# Generated by innovus_enablement/scripts/gen_innovus_lef.py from ../i3dPDK_NS3K/TECH/i3dPDK_NS3K_5T_mw.tf
# i3dPDK_NS3K v1.1 (CC BY-NC-SA 4.0, Prof. Taigon Song, I3D VLSI Lab, KNU)
# NOT part of the original PDK. Directions and R/C are
# assumptions (see gen_innovus_lef.py ASSUMPTIONS).
VERSION 5.8 ;
BUSBITCHARS "[]" ;
DIVIDERCHAR "/" ;

UNITS
  DATABASE MICRONS 2000 ;
END UNITS
MANUFACTURINGGRID 0.0005 ;

# Unidirectional variant: M2 M3 M4 preferred direction only, on track (see UNIDIR_*).
# Strictly unidirectional variant of i3dPDK_NS3K_5T_tech_unidir.lef (TECH_LEF=..., experiments):
# every metal from M5 up also takes RIGHTWAYONGRIDONLY + RECTONLY, so NanoRoute routes M2-M11 in the preferred
# direction only, on track, like the ICC2 flow (M5+ track offsets unchanged). 1x geometry (lef_x4/: 4x).
PROPERTYDEFINITIONS
  LAYER LEF58_RIGHTWAYONGRIDONLY STRING ;
  LAYER LEF58_RECTONLY STRING ;
END PROPERTYDEFINITIONS

SITE i3d_nsfet3nm
  CLASS CORE ;
  SYMMETRY Y ;
  SIZE 0.044 BY 0.12 ;
END i3d_nsfet3nm

SITE i3d_nsfet3nm_2H_VDD
  CLASS CORE ;
  SYMMETRY Y ;
  SIZE 0.044 BY 0.24 ;
END i3d_nsfet3nm_2H_VDD

SITE i3d_nsfet3nm_2H_VSS
  CLASS CORE ;
  SYMMETRY Y ;
  SIZE 0.044 BY 0.24 ;
END i3d_nsfet3nm_2H_VSS

SITE i3d_nsfet3nm_3H_VDD
  CLASS CORE ;
  SYMMETRY Y ;
  SIZE 0.044 BY 0.36 ;
END i3d_nsfet3nm_3H_VDD

SITE i3d_nsfet3nm_3H_VSS
  CLASS CORE ;
  SYMMETRY Y ;
  SIZE 0.044 BY 0.36 ;
END i3d_nsfet3nm_3H_VSS

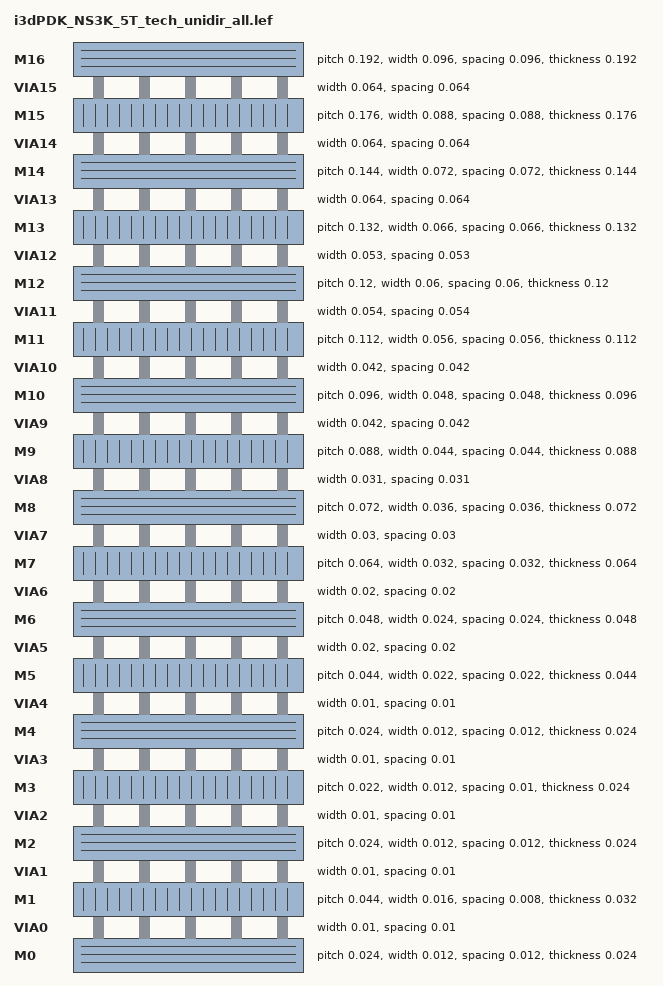
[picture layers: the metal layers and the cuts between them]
LAYER M0
  TYPE ROUTING ;
  DIRECTION HORIZONTAL ;
  PITCH 0.024 ;
  OFFSET 0.012 ;
  WIDTH 0.012 ;
  MINWIDTH 0.012 ;
  HEIGHT 0 ;
  THICKNESS 0.024 ;
  MAXWIDTH 5 ;
  SPACING 0.012 ;
  AREA 0.000144 ;
  RESISTANCE RPERSQ 8.0000 ;
  CAPACITANCE CPERSQDIST 0.00300000 ;
  EDGECAPACITANCE 0.00008000 ;
END M0

LAYER VIA0
  TYPE CUT ;
  WIDTH 0.01 ;
  SPACING 0.01 ;
  RESISTANCE 50.0000 ;
END VIA0

LAYER M1
  TYPE ROUTING ;
  DIRECTION VERTICAL ;
  PITCH 0.044 ;
  OFFSET 0.022 ;
  WIDTH 0.016 ;
  MINWIDTH 0.016 ;
  HEIGHT 0.048 ;
  THICKNESS 0.032 ;
  MAXWIDTH 5 ;
  SPACING 0.008 ;
  AREA 0.000256 ;
  RESISTANCE RPERSQ 8.0000 ;
  CAPACITANCE CPERSQDIST 0.00300000 ;
  EDGECAPACITANCE 0.00008000 ;
END M1

LAYER VIA1
  TYPE CUT ;
  WIDTH 0.01 ;
  SPACING 0.01 ;
  RESISTANCE 50.0000 ;
END VIA1

LAYER M2
  TYPE ROUTING ;
  DIRECTION HORIZONTAL ;
  PITCH 0.024 ;
  OFFSET 0 ;
  WIDTH 0.012 ;
  MINWIDTH 0.012 ;
  HEIGHT 0.112 ;
  THICKNESS 0.024 ;
  MAXWIDTH 5 ;
  SPACING 0.012 ;
  AREA 0.000144 ;
  RESISTANCE RPERSQ 8.0000 ;
  CAPACITANCE CPERSQDIST 0.00300000 ;
  EDGECAPACITANCE 0.00008000 ;
  PROPERTY LEF58_RIGHTWAYONGRIDONLY "RIGHTWAYONGRIDONLY ;" ;
  PROPERTY LEF58_RECTONLY "RECTONLY ;" ;
END M2

LAYER VIA2
  TYPE CUT ;
  WIDTH 0.01 ;
  SPACING 0.01 ;
  RESISTANCE 50.0000 ;
END VIA2

LAYER M3
  TYPE ROUTING ;
  DIRECTION VERTICAL ;
  PITCH 0.022 ;
  OFFSET 0 ;
  WIDTH 0.012 ;
  MINWIDTH 0.012 ;
  HEIGHT 0.16 ;
  THICKNESS 0.024 ;
  MAXWIDTH 5 ;
  SPACING 0.01 ;
  AREA 0.000144 ;
  RESISTANCE RPERSQ 8.0000 ;
  CAPACITANCE CPERSQDIST 0.00300000 ;
  EDGECAPACITANCE 0.00008000 ;
  PROPERTY LEF58_RIGHTWAYONGRIDONLY "RIGHTWAYONGRIDONLY ;" ;
  PROPERTY LEF58_RECTONLY "RECTONLY ;" ;
END M3

LAYER VIA3
  TYPE CUT ;
  WIDTH 0.01 ;
  SPACING 0.01 ;
  RESISTANCE 50.0000 ;
END VIA3

LAYER M4
  TYPE ROUTING ;
  DIRECTION HORIZONTAL ;
  PITCH 0.024 ;
  OFFSET 0 ;
  WIDTH 0.012 ;
  MINWIDTH 0.012 ;
  HEIGHT 0.208 ;
  THICKNESS 0.024 ;
  MAXWIDTH 5 ;
  SPACING 0.012 ;
  AREA 0.000144 ;
  RESISTANCE RPERSQ 1.2000 ;
  CAPACITANCE CPERSQDIST 0.00200000 ;
  EDGECAPACITANCE 0.00007000 ;
  PROPERTY LEF58_RIGHTWAYONGRIDONLY "RIGHTWAYONGRIDONLY ;" ;
  PROPERTY LEF58_RECTONLY "RECTONLY ;" ;
END M4

LAYER VIA4
  TYPE CUT ;
  WIDTH 0.01 ;
  SPACING 0.01 ;
  RESISTANCE 15.0000 ;
END VIA4

LAYER M5
  TYPE ROUTING ;
  DIRECTION VERTICAL ;
  PITCH 0.044 ;
  OFFSET 0.022 ;
  WIDTH 0.022 ;
  MINWIDTH 0.022 ;
  HEIGHT 0.256 ;
  THICKNESS 0.044 ;
  MAXWIDTH 5 ;
  SPACING 0.022 ;
  AREA 0.000484 ;
  RESISTANCE RPERSQ 1.2000 ;
  CAPACITANCE CPERSQDIST 0.00200000 ;
  EDGECAPACITANCE 0.00007000 ;
  PROPERTY LEF58_RIGHTWAYONGRIDONLY "RIGHTWAYONGRIDONLY ;" ;
  PROPERTY LEF58_RECTONLY "RECTONLY ;" ;
END M5

LAYER VIA5
  TYPE CUT ;
  WIDTH 0.02 ;
  SPACING 0.02 ;
  RESISTANCE 15.0000 ;
END VIA5

LAYER M6
  TYPE ROUTING ;
  DIRECTION HORIZONTAL ;
  PITCH 0.048 ;
  OFFSET 0.024 ;
  WIDTH 0.024 ;
  MINWIDTH 0.024 ;
  HEIGHT 0.344 ;
  THICKNESS 0.048 ;
  MAXWIDTH 5 ;
  SPACING 0.024 ;
  AREA 0.000576 ;
  RESISTANCE RPERSQ 1.2000 ;
  CAPACITANCE CPERSQDIST 0.00200000 ;
  EDGECAPACITANCE 0.00007000 ;
  PROPERTY LEF58_RIGHTWAYONGRIDONLY "RIGHTWAYONGRIDONLY ;" ;
  PROPERTY LEF58_RECTONLY "RECTONLY ;" ;
END M6

LAYER VIA6
  TYPE CUT ;
  WIDTH 0.02 ;
  SPACING 0.02 ;
  RESISTANCE 15.0000 ;
END VIA6

LAYER M7
  TYPE ROUTING ;
  DIRECTION VERTICAL ;
  PITCH 0.064 ;
  OFFSET 0.032 ;
  WIDTH 0.032 ;
  MINWIDTH 0.032 ;
  HEIGHT 0.44 ;
  THICKNESS 0.064 ;
  MAXWIDTH 5 ;
  SPACING 0.032 ;
  AREA 0.001024 ;
  RESISTANCE RPERSQ 1.2000 ;
  CAPACITANCE CPERSQDIST 0.00200000 ;
  EDGECAPACITANCE 0.00007000 ;
  PROPERTY LEF58_RIGHTWAYONGRIDONLY "RIGHTWAYONGRIDONLY ;" ;
  PROPERTY LEF58_RECTONLY "RECTONLY ;" ;
END M7

LAYER VIA7
  TYPE CUT ;
  WIDTH 0.03 ;
  SPACING 0.03 ;
  RESISTANCE 15.0000 ;
END VIA7

LAYER M8
  TYPE ROUTING ;
  DIRECTION HORIZONTAL ;
  PITCH 0.072 ;
  OFFSET 0.036 ;
  WIDTH 0.036 ;
  MINWIDTH 0.036 ;
  HEIGHT 0.568 ;
  THICKNESS 0.072 ;
  MAXWIDTH 5 ;
  SPACING 0.036 ;
  AREA 0.001296 ;
  RESISTANCE RPERSQ 1.0000 ;
  CAPACITANCE CPERSQDIST 0.00200000 ;
  EDGECAPACITANCE 0.00007000 ;
  PROPERTY LEF58_RIGHTWAYONGRIDONLY "RIGHTWAYONGRIDONLY ;" ;
  PROPERTY LEF58_RECTONLY "RECTONLY ;" ;
END M8

LAYER VIA8
  TYPE CUT ;
  WIDTH 0.031 ;
  SPACING 0.031 ;
  RESISTANCE 10.0000 ;
END VIA8

LAYER M9
  TYPE ROUTING ;
  DIRECTION VERTICAL ;
  PITCH 0.088 ;
  OFFSET 0.044 ;
  WIDTH 0.044 ;
  MINWIDTH 0.044 ;
  HEIGHT 0.712 ;
  THICKNESS 0.088 ;
  MAXWIDTH 5 ;
  SPACING 0.044 ;
  AREA 0.001936 ;
  RESISTANCE RPERSQ 1.0000 ;
  CAPACITANCE CPERSQDIST 0.00200000 ;
  EDGECAPACITANCE 0.00007000 ;
  PROPERTY LEF58_RIGHTWAYONGRIDONLY "RIGHTWAYONGRIDONLY ;" ;
  PROPERTY LEF58_RECTONLY "RECTONLY ;" ;
END M9

LAYER VIA9
  TYPE CUT ;
  WIDTH 0.042 ;
  SPACING 0.042 ;
  RESISTANCE 10.0000 ;
END VIA9

LAYER M10
  TYPE ROUTING ;
  DIRECTION HORIZONTAL ;
  PITCH 0.096 ;
  OFFSET 0.048 ;
  WIDTH 0.048 ;
  MINWIDTH 0.048 ;
  HEIGHT 0.888 ;
  THICKNESS 0.096 ;
  MAXWIDTH 5 ;
  SPACING 0.048 ;
  AREA 0.002304 ;
  RESISTANCE RPERSQ 1.0000 ;
  CAPACITANCE CPERSQDIST 0.00200000 ;
  EDGECAPACITANCE 0.00007000 ;
  PROPERTY LEF58_RIGHTWAYONGRIDONLY "RIGHTWAYONGRIDONLY ;" ;
  PROPERTY LEF58_RECTONLY "RECTONLY ;" ;
END M10

LAYER VIA10
  TYPE CUT ;
  WIDTH 0.042 ;
  SPACING 0.042 ;
  RESISTANCE 10.0000 ;
END VIA10

LAYER M11
  TYPE ROUTING ;
  DIRECTION VERTICAL ;
  PITCH 0.112 ;
  OFFSET 0.056 ;
  WIDTH 0.056 ;
  MINWIDTH 0.056 ;
  HEIGHT 1.08 ;
  THICKNESS 0.112 ;
  MAXWIDTH 5 ;
  SPACING 0.056 ;
  AREA 0.003136 ;
  RESISTANCE RPERSQ 1.0000 ;
  CAPACITANCE CPERSQDIST 0.00200000 ;
  EDGECAPACITANCE 0.00007000 ;
  PROPERTY LEF58_RIGHTWAYONGRIDONLY "RIGHTWAYONGRIDONLY ;" ;
  PROPERTY LEF58_RECTONLY "RECTONLY ;" ;
END M11

LAYER VIA11
  TYPE CUT ;
  WIDTH 0.054 ;
  SPACING 0.054 ;
  RESISTANCE 10.0000 ;
END VIA11

LAYER M12
  TYPE ROUTING ;
  DIRECTION HORIZONTAL ;
  PITCH 0.12 ;
  OFFSET 0.06 ;
  WIDTH 0.06 ;
  MINWIDTH 0.06 ;
  HEIGHT 1.304 ;
  THICKNESS 0.12 ;
  MAXWIDTH 5 ;
  SPACING 0.06 ;
  AREA 0.003600 ;
  RESISTANCE RPERSQ 0.1000 ;
  CAPACITANCE CPERSQDIST 0.00100000 ;
  EDGECAPACITANCE 0.00006000 ;
  PROPERTY LEF58_RIGHTWAYONGRIDONLY "RIGHTWAYONGRIDONLY ;" ;
  PROPERTY LEF58_RECTONLY "RECTONLY ;" ;
END M12

LAYER VIA12
  TYPE CUT ;
  WIDTH 0.053 ;
  SPACING 0.053 ;
  RESISTANCE 2.0000 ;
END VIA12

LAYER M13
  TYPE ROUTING ;
  DIRECTION VERTICAL ;
  PITCH 0.132 ;
  OFFSET 0.066 ;
  WIDTH 0.066 ;
  MINWIDTH 0.066 ;
  HEIGHT 1.544 ;
  THICKNESS 0.132 ;
  MAXWIDTH 5 ;
  SPACING 0.066 ;
  AREA 0.004356 ;
  RESISTANCE RPERSQ 0.1000 ;
  CAPACITANCE CPERSQDIST 0.00100000 ;
  EDGECAPACITANCE 0.00006000 ;
  PROPERTY LEF58_RIGHTWAYONGRIDONLY "RIGHTWAYONGRIDONLY ;" ;
  PROPERTY LEF58_RECTONLY "RECTONLY ;" ;
END M13

LAYER VIA13
  TYPE CUT ;
  WIDTH 0.064 ;
  SPACING 0.064 ;
  RESISTANCE 2.0000 ;
END VIA13

LAYER M14
  TYPE ROUTING ;
  DIRECTION HORIZONTAL ;
  PITCH 0.144 ;
  OFFSET 0.072 ;
  WIDTH 0.072 ;
  MINWIDTH 0.072 ;
  HEIGHT 1.808 ;
  THICKNESS 0.144 ;
  MAXWIDTH 5 ;
  SPACING 0.072 ;
  AREA 0.005184 ;
  RESISTANCE RPERSQ 0.1000 ;
  CAPACITANCE CPERSQDIST 0.00100000 ;
  EDGECAPACITANCE 0.00006000 ;
  PROPERTY LEF58_RIGHTWAYONGRIDONLY "RIGHTWAYONGRIDONLY ;" ;
  PROPERTY LEF58_RECTONLY "RECTONLY ;" ;
END M14

LAYER VIA14
  TYPE CUT ;
  WIDTH 0.064 ;
  SPACING 0.064 ;
  RESISTANCE 2.0000 ;
END VIA14

LAYER M15
  TYPE ROUTING ;
  DIRECTION VERTICAL ;
  PITCH 0.176 ;
  OFFSET 0.088 ;
  WIDTH 0.088 ;
  MINWIDTH 0.088 ;
  HEIGHT 2.096 ;
  THICKNESS 0.176 ;
  MAXWIDTH 5 ;
  SPACING 0.088 ;
  AREA 0.007744 ;
  RESISTANCE RPERSQ 0.0300 ;
  CAPACITANCE CPERSQDIST 0.00050000 ;
  EDGECAPACITANCE 0.00005000 ;
  PROPERTY LEF58_RIGHTWAYONGRIDONLY "RIGHTWAYONGRIDONLY ;" ;
  PROPERTY LEF58_RECTONLY "RECTONLY ;" ;
END M15

LAYER VIA15
  TYPE CUT ;
  WIDTH 0.064 ;
  SPACING 0.064 ;
  RESISTANCE 0.5000 ;
END VIA15

LAYER M16
  TYPE ROUTING ;
  DIRECTION HORIZONTAL ;
  PITCH 0.192 ;
  OFFSET 0.096 ;
  WIDTH 0.096 ;
  MINWIDTH 0.096 ;
  HEIGHT 2.448 ;
  THICKNESS 0.192 ;
  MAXWIDTH 5 ;
  SPACING 0.096 ;
  AREA 0.009216 ;
  RESISTANCE RPERSQ 0.0300 ;
  CAPACITANCE CPERSQDIST 0.00050000 ;
  EDGECAPACITANCE 0.00005000 ;
  PROPERTY LEF58_RIGHTWAYONGRIDONLY "RIGHTWAYONGRIDONLY ;" ;
  PROPERTY LEF58_RECTONLY "RECTONLY ;" ;
END M16

VIA VIA01 DEFAULT
  RESISTANCE 50.0000 ;
  LAYER M0 ;
    RECT -0.006 -0.006 0.006 0.006 ;
  LAYER VIA0 ;
    RECT -0.005 -0.005 0.005 0.005 ;
  LAYER M1 ;
    RECT -0.008 -0.008 0.008 0.008 ;
END VIA01

VIA VIA12 DEFAULT
  RESISTANCE 50.0000 ;
  LAYER M1 ;
    RECT -0.008 -0.008 0.008 0.008 ;
  LAYER VIA1 ;
    RECT -0.005 -0.005 0.005 0.005 ;
  LAYER M2 ;
    RECT -0.006 -0.006 0.006 0.006 ;
END VIA12

VIA VIA23 DEFAULT
  RESISTANCE 50.0000 ;
  LAYER M2 ;
    RECT -0.006 -0.006 0.006 0.006 ;
  LAYER VIA2 ;
    RECT -0.005 -0.005 0.005 0.005 ;
  LAYER M3 ;
    RECT -0.006 -0.006 0.006 0.006 ;
END VIA23

VIA VIA34 DEFAULT
  RESISTANCE 50.0000 ;
  LAYER M3 ;
    RECT -0.006 -0.006 0.006 0.006 ;
  LAYER VIA3 ;
    RECT -0.005 -0.005 0.005 0.005 ;
  LAYER M4 ;
    RECT -0.006 -0.006 0.006 0.006 ;
END VIA34

VIA VIA45 DEFAULT
  RESISTANCE 15.0000 ;
  LAYER M4 ;
    RECT -0.006 -0.006 0.006 0.006 ;
  LAYER VIA4 ;
    RECT -0.005 -0.005 0.005 0.005 ;
  LAYER M5 ;
    RECT -0.011 -0.011 0.011 0.011 ;
END VIA45

VIA VIA56 DEFAULT
  RESISTANCE 15.0000 ;
  LAYER M5 ;
    RECT -0.011 -0.011 0.011 0.011 ;
  LAYER VIA5 ;
    RECT -0.01 -0.01 0.01 0.01 ;
  LAYER M6 ;
    RECT -0.012 -0.012 0.012 0.012 ;
END VIA56

VIA VIA67 DEFAULT
  RESISTANCE 15.0000 ;
  LAYER M6 ;
    RECT -0.012 -0.012 0.012 0.012 ;
  LAYER VIA6 ;
    RECT -0.01 -0.01 0.01 0.01 ;
  LAYER M7 ;
    RECT -0.016 -0.016 0.016 0.016 ;
END VIA67

VIA VIA78 DEFAULT
  RESISTANCE 15.0000 ;
  LAYER M7 ;
    RECT -0.0165 -0.0165 0.0165 0.0165 ;
  LAYER VIA7 ;
    RECT -0.0155 -0.0155 0.0155 0.0155 ;
  LAYER M8 ;
    RECT -0.018 -0.018 0.018 0.018 ;
END VIA78

VIA VIA89 DEFAULT
  RESISTANCE 10.0000 ;
  LAYER M8 ;
    RECT -0.018 -0.018 0.018 0.018 ;
  LAYER VIA8 ;
    RECT -0.0155 -0.0155 0.0155 0.0155 ;
  LAYER M9 ;
    RECT -0.022 -0.022 0.022 0.022 ;
END VIA89

VIA VIA910 DEFAULT
  RESISTANCE 10.0000 ;
  LAYER M9 ;
    RECT -0.022 -0.022 0.022 0.022 ;
  LAYER VIA9 ;
    RECT -0.021 -0.021 0.021 0.021 ;
  LAYER M10 ;
    RECT -0.024 -0.024 0.024 0.024 ;
END VIA910

VIA VIA1011 DEFAULT
  RESISTANCE 10.0000 ;
  LAYER M10 ;
    RECT -0.024 -0.024 0.024 0.024 ;
  LAYER VIA10 ;
    RECT -0.021 -0.021 0.021 0.021 ;
  LAYER M11 ;
    RECT -0.028 -0.028 0.028 0.028 ;
END VIA1011

VIA VIA1112 DEFAULT
  RESISTANCE 10.0000 ;
  LAYER M11 ;
    RECT -0.028 -0.028 0.028 0.028 ;
  LAYER VIA11 ;
    RECT -0.0265 -0.0265 0.0265 0.0265 ;
  LAYER M12 ;
    RECT -0.03 -0.03 0.03 0.03 ;
END VIA1112

VIA via1213 DEFAULT
  RESISTANCE 2.0000 ;
  LAYER M12 ;
    RECT -0.03 -0.03 0.03 0.03 ;
  LAYER VIA12 ;
    RECT -0.0265 -0.0265 0.0265 0.0265 ;
  LAYER M13 ;
    RECT -0.033 -0.033 0.033 0.033 ;
END via1213

VIA via1314 DEFAULT
  RESISTANCE 2.0000 ;
  LAYER M13 ;
    RECT -0.033 -0.033 0.033 0.033 ;
  LAYER VIA13 ;
    RECT -0.032 -0.032 0.032 0.032 ;
  LAYER M14 ;
    RECT -0.036 -0.036 0.036 0.036 ;
END via1314

VIA via1415 DEFAULT
  RESISTANCE 2.0000 ;
  LAYER M14 ;
    RECT -0.036 -0.036 0.036 0.036 ;
  LAYER VIA14 ;
    RECT -0.032 -0.032 0.032 0.032 ;
  LAYER M15 ;
    RECT -0.044 -0.044 0.044 0.044 ;
END via1415

VIA via1516 DEFAULT
  RESISTANCE 0.5000 ;
  LAYER M15 ;
    RECT -0.044 -0.044 0.044 0.044 ;
  LAYER VIA15 ;
    RECT -0.032 -0.032 0.032 0.032 ;
  LAYER M16 ;
    RECT -0.048 -0.048 0.048 0.048 ;
END via1516

VIARULE VIA01_gen GENERATE
  LAYER M0 ;
    ENCLOSURE 0.001 0.001 ;
  LAYER M1 ;
    ENCLOSURE 0.003 0.003 ;
  LAYER VIA0 ;
    RECT -0.005 -0.005 0.005 0.005 ;
    SPACING 0.02 BY 0.02 ;
END VIA01_gen

VIARULE VIA12_gen GENERATE
  LAYER M1 ;
    ENCLOSURE 0.003 0.003 ;
  LAYER M2 ;
    ENCLOSURE 0.001 0.001 ;
  LAYER VIA1 ;
    RECT -0.005 -0.005 0.005 0.005 ;
    SPACING 0.02 BY 0.02 ;
END VIA12_gen

VIARULE VIA23_gen GENERATE
  LAYER M2 ;
    ENCLOSURE 0.001 0.001 ;
  LAYER M3 ;
    ENCLOSURE 0.001 0.001 ;
  LAYER VIA2 ;
    RECT -0.005 -0.005 0.005 0.005 ;
    SPACING 0.02 BY 0.02 ;
END VIA23_gen

VIARULE VIA34_gen GENERATE
  LAYER M3 ;
    ENCLOSURE 0.001 0.001 ;
  LAYER M4 ;
    ENCLOSURE 0.001 0.001 ;
  LAYER VIA3 ;
    RECT -0.005 -0.005 0.005 0.005 ;
    SPACING 0.02 BY 0.02 ;
END VIA34_gen

VIARULE VIA45_gen GENERATE
  LAYER M4 ;
    ENCLOSURE 0.001 0.001 ;
  LAYER M5 ;
    ENCLOSURE 0.006 0.006 ;
  LAYER VIA4 ;
    RECT -0.005 -0.005 0.005 0.005 ;
    SPACING 0.02 BY 0.02 ;
END VIA45_gen

VIARULE VIA56_gen GENERATE
  LAYER M5 ;
    ENCLOSURE 0.001 0.001 ;
  LAYER M6 ;
    ENCLOSURE 0.002 0.002 ;
  LAYER VIA5 ;
    RECT -0.01 -0.01 0.01 0.01 ;
    SPACING 0.04 BY 0.04 ;
END VIA56_gen

VIARULE VIA67_gen GENERATE
  LAYER M6 ;
    ENCLOSURE 0.002 0.002 ;
  LAYER M7 ;
    ENCLOSURE 0.006 0.006 ;
  LAYER VIA6 ;
    RECT -0.01 -0.01 0.01 0.01 ;
    SPACING 0.04 BY 0.04 ;
END VIA67_gen

VIARULE VIA78_gen GENERATE
  LAYER M7 ;
    ENCLOSURE 0.001 0.001 ;
  LAYER M8 ;
    ENCLOSURE 0.002 0.002 ;
  LAYER VIA7 ;
    RECT -0.0155 -0.0155 0.0155 0.0155 ;
    SPACING 0.062 BY 0.062 ;
END VIA78_gen

VIARULE VIA89_gen GENERATE
  LAYER M8 ;
    ENCLOSURE 0.002 0.002 ;
  LAYER M9 ;
    ENCLOSURE 0.006 0.006 ;
  LAYER VIA8 ;
    RECT -0.0155 -0.0155 0.0155 0.0155 ;
    SPACING 0.062 BY 0.062 ;
END VIA89_gen

VIARULE VIA910_gen GENERATE
  LAYER M9 ;
    ENCLOSURE 0.001 0.001 ;
  LAYER M10 ;
    ENCLOSURE 0.003 0.003 ;
  LAYER VIA9 ;
    RECT -0.021 -0.021 0.021 0.021 ;
    SPACING 0.084 BY 0.084 ;
END VIA910_gen

VIARULE VIA1011_gen GENERATE
  LAYER M10 ;
    ENCLOSURE 0.003 0.003 ;
  LAYER M11 ;
    ENCLOSURE 0.006 0.006 ;
  LAYER VIA10 ;
    RECT -0.021 -0.021 0.021 0.021 ;
    SPACING 0.084 BY 0.084 ;
END VIA1011_gen

VIARULE VIA1112_gen GENERATE
  LAYER M11 ;
    ENCLOSURE 0.001 0.001 ;
  LAYER M12 ;
    ENCLOSURE 0.003 0.003 ;
  LAYER VIA11 ;
    RECT -0.0265 -0.0265 0.0265 0.0265 ;
    SPACING 0.106 BY 0.106 ;
END VIA1112_gen

VIARULE via1213_gen GENERATE
  LAYER M12 ;
    ENCLOSURE 0.003 0.003 ;
  LAYER M13 ;
    ENCLOSURE 0.006 0.006 ;
  LAYER VIA12 ;
    RECT -0.0265 -0.0265 0.0265 0.0265 ;
    SPACING 0.106 BY 0.106 ;
END via1213_gen

VIARULE via1314_gen GENERATE
  LAYER M13 ;
    ENCLOSURE 0.001 0.001 ;
  LAYER M14 ;
    ENCLOSURE 0.004 0.004 ;
  LAYER VIA13 ;
    RECT -0.032 -0.032 0.032 0.032 ;
    SPACING 0.128 BY 0.128 ;
END via1314_gen

VIARULE via1415_gen GENERATE
  LAYER M14 ;
    ENCLOSURE 0.004 0.004 ;
  LAYER M15 ;
    ENCLOSURE 0.012 0.012 ;
  LAYER VIA14 ;
    RECT -0.032 -0.032 0.032 0.032 ;
    SPACING 0.128 BY 0.128 ;
END via1415_gen

VIARULE via1516_gen GENERATE
  LAYER M15 ;
    ENCLOSURE 0.012 0.012 ;
  LAYER M16 ;
    ENCLOSURE 0.016 0.016 ;
  LAYER VIA15 ;
    RECT -0.032 -0.032 0.032 0.032 ;
    SPACING 0.128 BY 0.128 ;
END via1516_gen

END LIBRARY
